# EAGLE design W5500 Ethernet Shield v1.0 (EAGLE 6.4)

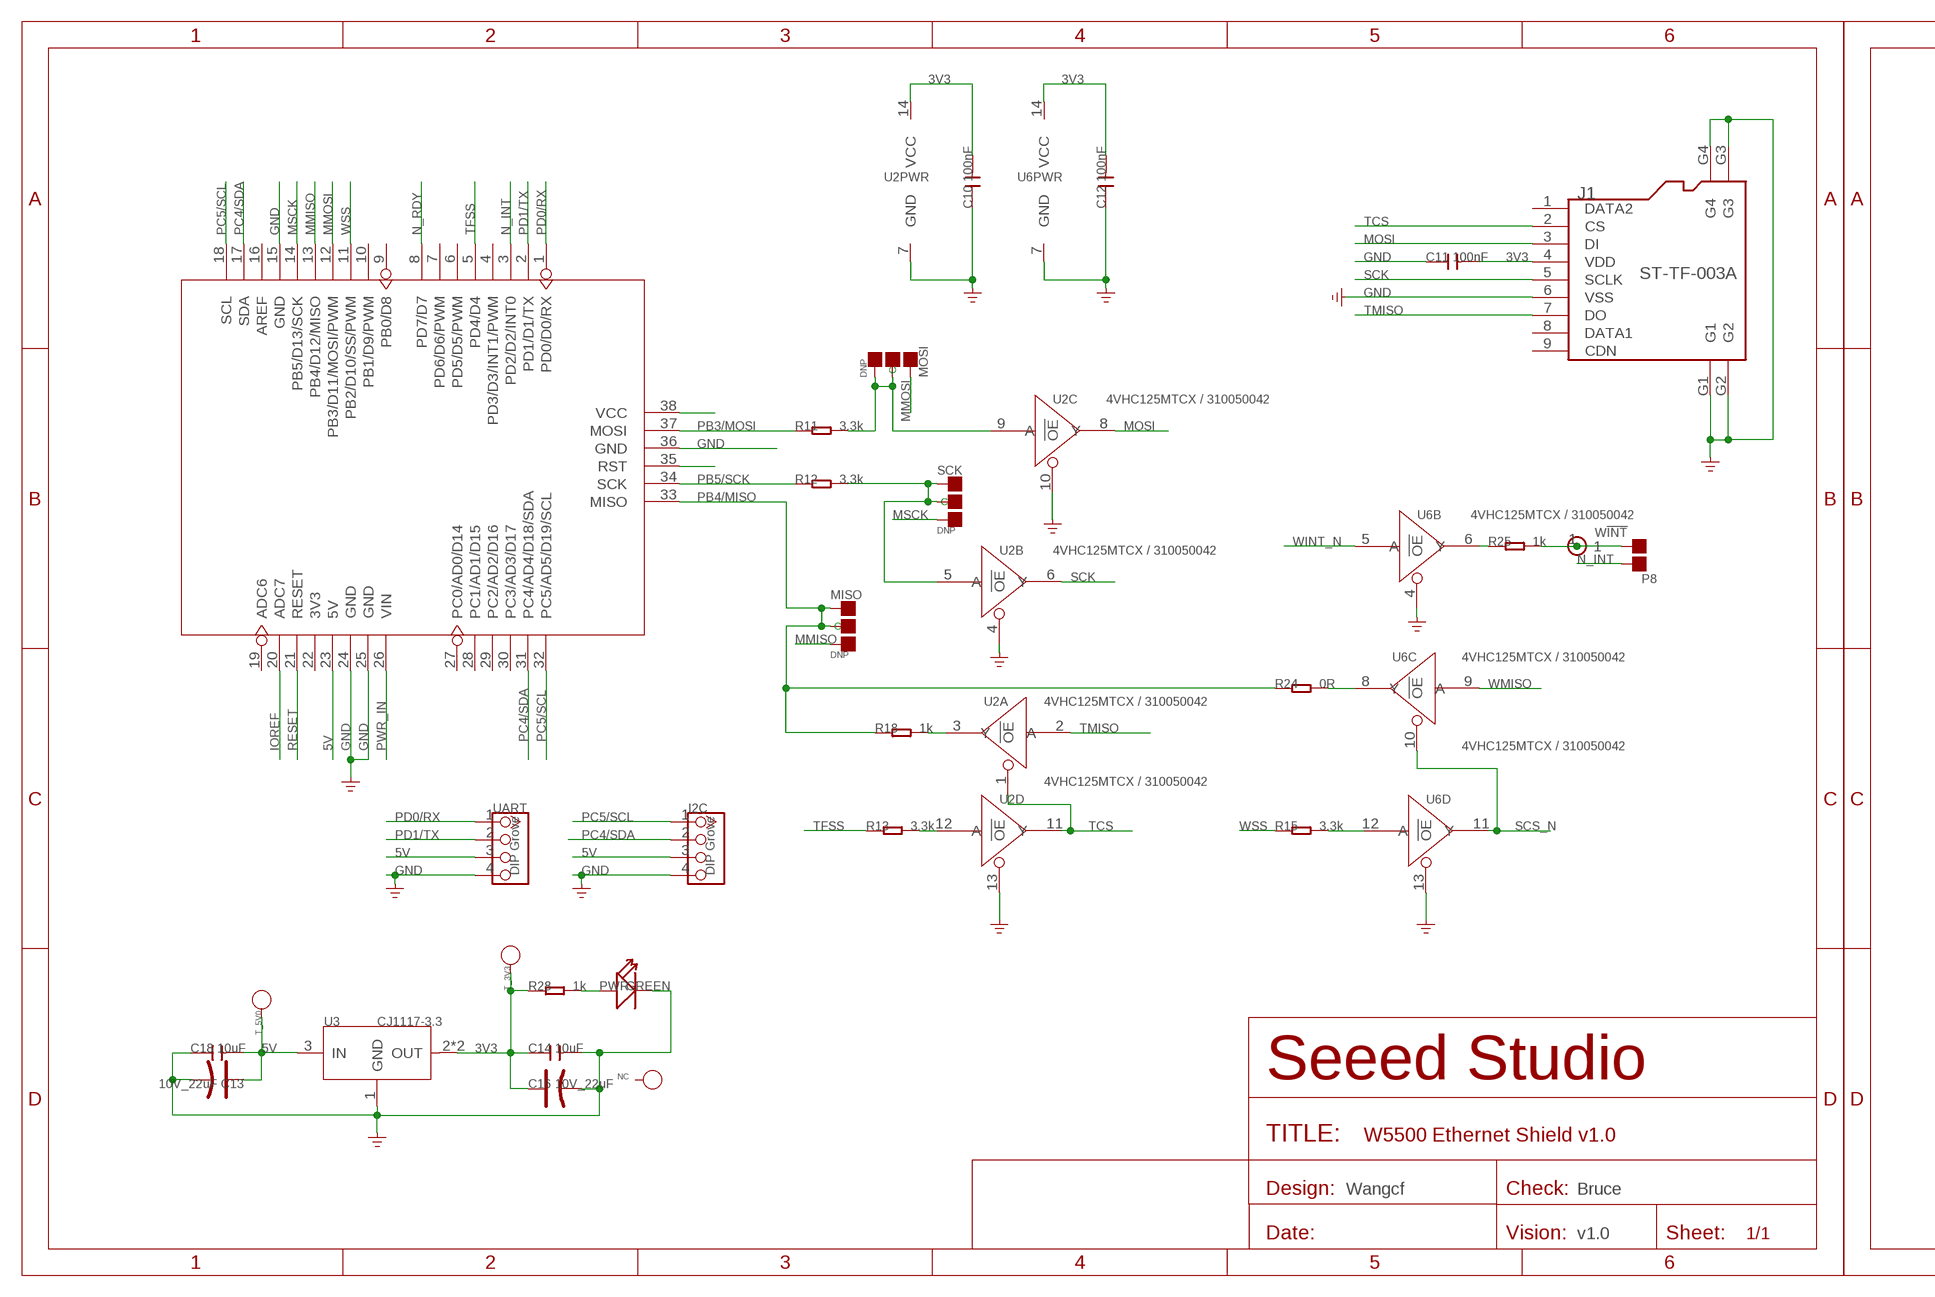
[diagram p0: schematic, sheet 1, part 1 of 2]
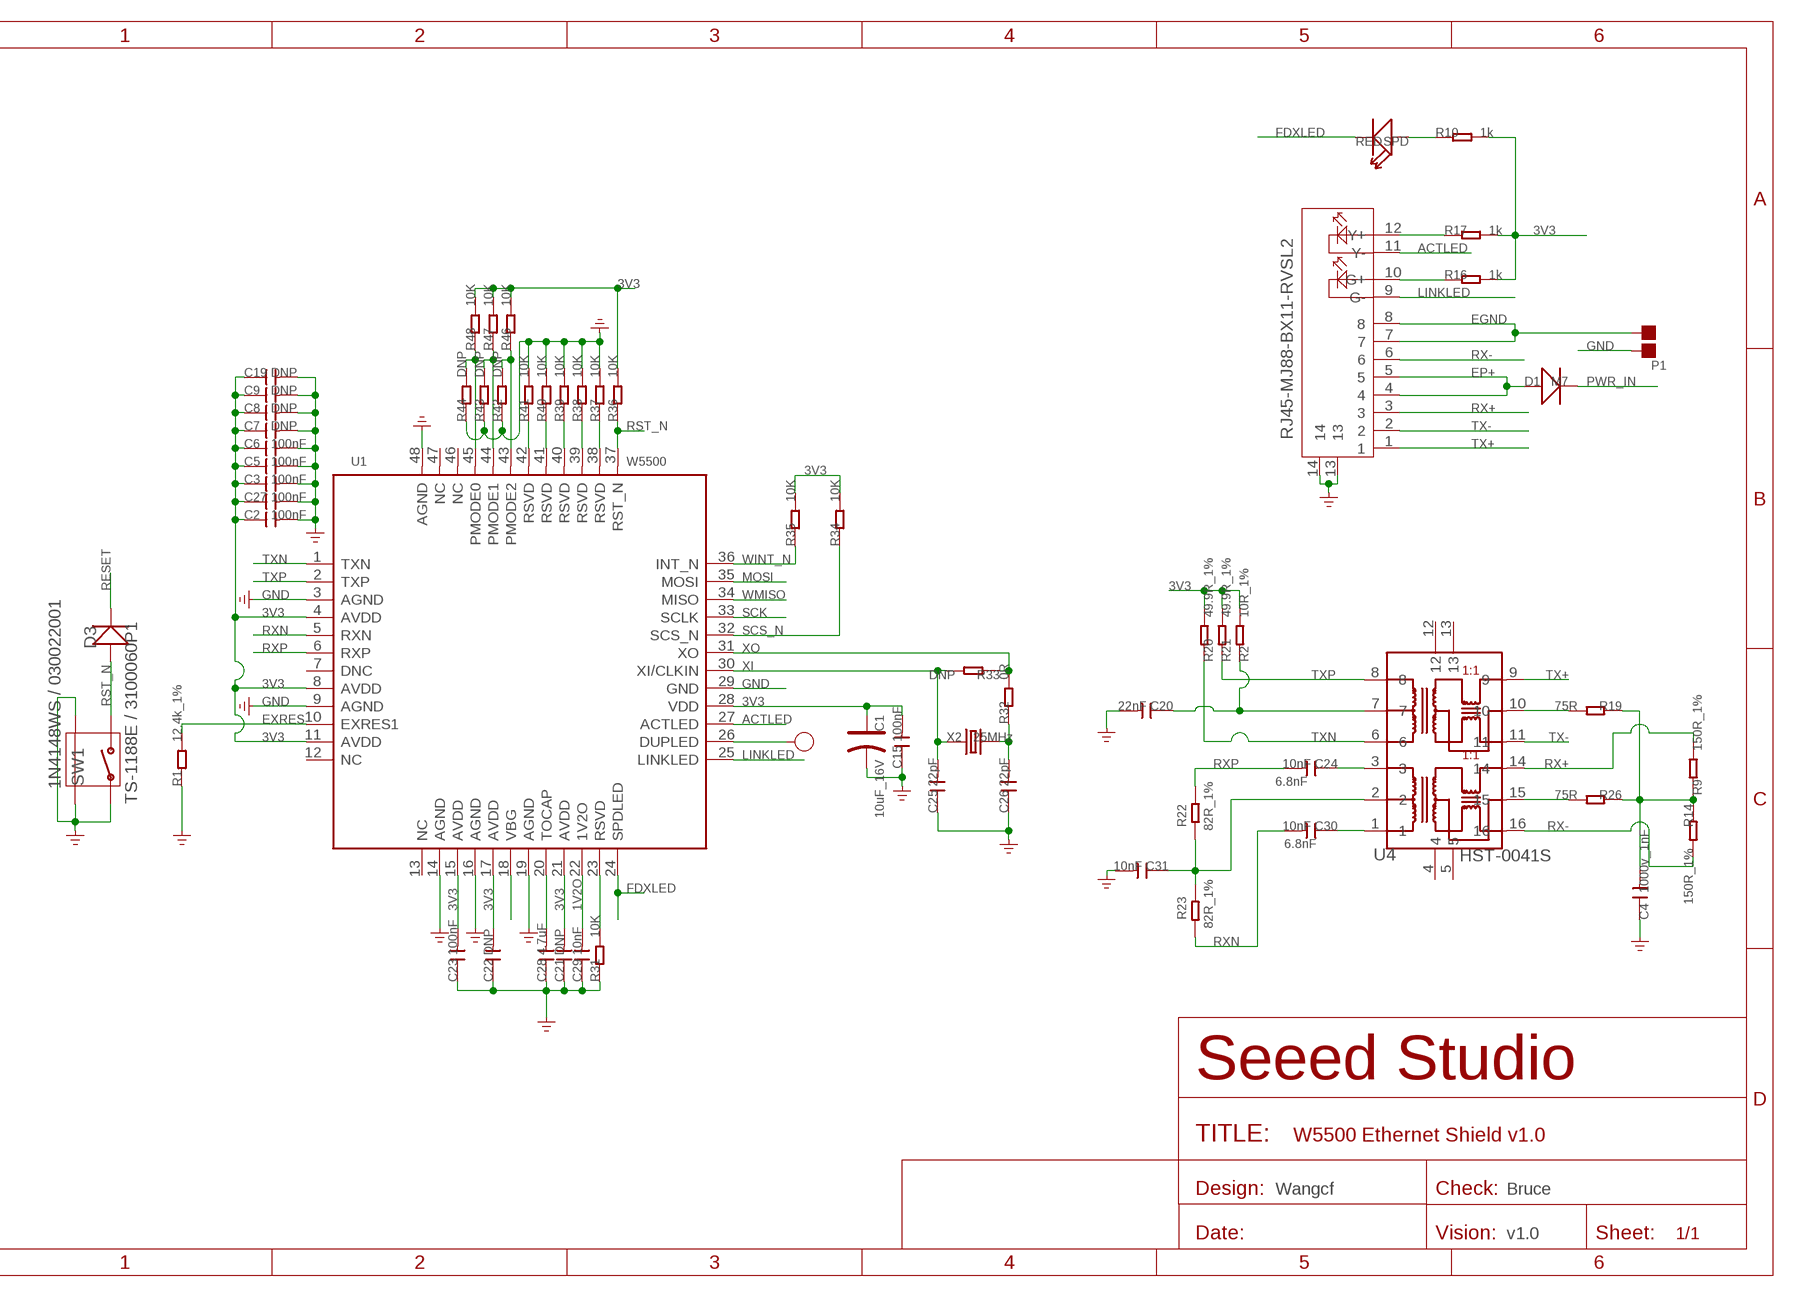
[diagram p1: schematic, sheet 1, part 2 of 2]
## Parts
C1  10uF_16V  CAP-POLAR-AVX-A  [AVX-A]
C2  100nF  C-0603  [C0603]
C3  100nF  C-0603  [C0603]
C4  1000v_1nF  C-1206  [C1206]
C5  100nF  C-0603  [C0603]
C6  100nF  C-0603  [C0603]
C7  DNP  C-0805  [C0805]
C8  DNP  C-0805  [C0805]
C9  DNP  C-0805  [C0805]
C10  100nF  C-0603  [C0603]
C11  100nF  C-0603  [C0603]
C12  100nF  C-0603  [C0603]
C13  10V_22uF  CAP-AVX-B  [AVX-B]
C14  10uF  C-0805  [C0805]
C15  100nF  C-0603  [C0603]
C16  10V_22uF  CAP-AVX-B  [AVX-B]
C18  10uF  C-0805  [C0805]
C19  DNP  C-0805  [C0805]
C20  22nF  C-0603  [C0603]
C21  DNP  C-0603  [C0603]
C22  DNP  C-0603  [C0603]
C23  100nF  C-0603  [C0603]
C24  10nF  C-0603  [C0603]
C25  22pF  C-0603  [C0603]
C26  22pF  C-0603  [C0603]
C27  100nF  C-0603  [C0603]
C28  4.7uF  C-0805  [C0805]
C29  10nF  C-0603  [C0603]
C30  10nF  C-0603  [C0603]
C31  10nF  C-0603  [C0603]
D1  M7  D'SMA'  [DO-214AC]
D3  1N4148WS / 030022001  D'0805'  [SOD323]
I2C  DIP Grove  TWIG-4P-2.0-2.0  [4P-2.0]
J1  ST-TF-003A  HOLDER-MICROSD-9P  [9P-SMD-W/-RING]
J8  RJ45-MJ88-BX11-RVSL2  [RJ45-MJ88-BX11-RVSL2]
MISO  DNP  PAD-JUMPER-3P-40*40  [3P-SMD-4.1X1.5]
MOSI  DNP  PAD-JUMPER-3P-40*40  [3P-SMD-4.1X1.5]
NC  PAD-TEST-POINT'4545'  [TP_4545]
P1  DNP  PAD-JUMPER-2P  [2P-SMD-1.78X1.27]
P8  DNP  PAD-JUMPER-2P  [2P-SMD-1.78X1.27]
PWR  GREEN  LED'0603'  [LED-0603]
R1  12.4k_1%  R-0603  [R0603]
R2  10R_1%  R-0603  [R0603]
R9  150R_1%  R-0603  [R0603]
R10  1k  R-0603  [R0603]
R11  3.3k  R-0603  [R0603]
R12  3.3k  R-0603  [R0603]
R13  3.3k  R-0603  [R0603]
R14  150R_1%  R-0603  [R0603]
R15  3.3k  R-0603  [R0603]
R16  1k  R-0603  [R0603]
R17  1k  R-0603  [R0603]
R18  1k  R-0603  [R0603]
R19  75R  R-0603  [R0603]
R20  49.9R_1%  R-0603  [R0603]
R21  49.9R_1%  R-0603  [R0603]
R22  82R_1%  R-0603  [R0603]
R23  82R_1%  R-0603  [R0603]
R24  0R  R-0603  [R0603]
R25  1k  R-0603  [R0603]
R26  75R  R-0603  [R0603]
R28  1k  R-0603  [R0603]
R31  10K  R-0603  [R0603]
R32  0R  R-0603  [R0603]
R33  DNP  R-0603  [R0603]
R34  10K  R-0603  [R0603]
R35  10K  R-0603  [R0603]
R36  10K  R-0603  [R0603]
R37  10K  R-0603  [R0603]
R38  10K  R-0603  [R0603]
R39  10K  R-0603  [R0603]
R40  10K  R-0603  [R0603]
R41  10K  R-0603  [R0603]
R42  DNP  R-0603  [R0603]
R43  DNP  R-0603  [R0603]
R44  DNP  R-0603  [R0603]
R46  10K  R-0603  [R0603]
R47  10K  R-0603  [R0603]
R48  10K  R-0603  [R0603]
SCK  DNP  PAD-JUMPER-3P-40*40  [3P-SMD-4.1X1.5]
SPD  RED  LED'0603'  [LED-0603]
SW1  TS-1188E / 3100060P1  BUTTON_4P_SMD  [4P-SMD-7X3.5X3.5]
T_3V3  PAD-TEST-POINT'4545'  [TP_4545]
T_5V0  PAD-TEST-POINT'4545'  [TP_4545]
TP6  PAD-TEST-POINT'4545'  [TP_4545]
U1  W5500  DRIVER-W5500  [LQFP-48]
U2  4VHC125MTCX / 310050042  74VHC125PW  [TSSOP14]
U3  CJ1117-3.3  LD1117S  [SOT-223]
U4  HST-0041S  [SOIC16-9.53]
U5  DNP  ARDUINO-38P'WITH-SILK'  [ARDUINO-DRILL-DIM]
U6  4VHC125MTCX / 310050042  74VHC125PW  [TSSOP14]
UART  DIP Grove  TWIG-4P-2.0-2.0  [4P-2.0]
W!INT  DNP  HEADER-1P-35  [1P-65/35MIL]
X2  25MHz  CRYSTAL'5032'  [2P-SMD-5X3.2]

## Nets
1V2O: C29.2 U1.22(1V2O)
3V3: C1.+ C2.1 C3.1 C5.1 C6.1 C7.1 C8.1 C9.1 C10.2 C11.2 C12.2 C14.1 C15.2 C16.+ C19.1 C21.2 C22.2 C23.2 C27.1 J1.4(VDD) R2.2 R10.2 R16.2 R17.2 R20.2 R21.2 R28.1 R34.2 R35.2 R36.2 R46.2 R47.2 R48.2 T_3V3.T U1.4(AVDD) U1.8(AVDD) U1.11(AVDD) U1.15(AVDD) U1.17(AVDD) U1.21(AVDD) U1.28(VDD) U2.14(PWR:VCC) U3.2(OUT) U3.TER(OUT) U6.14(PWR:VCC)
5V [usbvcc]: C13.+ C18.2 I2C.3 T_5V0.T U3.3(IN) U5.23(5V) UART.3
ACTLED: J8.11(Y-) U1.27(ACTLED)
EGND [power]: J8.7 J8.8 P1.1
EP+: D1.1(+) J8.4 J8.5
EXRES: R1.2 U1.10(EXRES1)
FDXLED: SPD.- U1.24(SPDLED)
GND: C1.- C2.2 C3.2 C4.1 C5.2 C6.2 C7.2 C8.2 C9.2 C10.1 C11.1 C12.1 C13.- C14.2 C15.1 C16.- C18.1 C19.2 C20.2 C21.1 C22.1 C23.1 C25.1 C26.1 C27.2 C28.1 C29.1 C31.2 I2C.4 J1.6(VSS) J1.G1 J1.G2 J1.G3 J1.G4 J8.13 J8.14 P1.2 PWR.- R1.1 R31.1 R37.2 R38.2 R39.2 R40.2 R41.2 R42.1 R43.1 R44.1 SW1.1 SW1.S1 SW1.S2 U1.3(AGND) U1.9(AGND) U1.14(AGND) U1.16(AGND) U1.19(AGND) U1.29(GND) U1.48(AGND) U2.4(B:!OE) U2.7(PWR:GND) U2.10(C:!OE) U2.13(D:!OE) U3.1(GND) U5.15(GND) U5.24(GND) U5.25(GND) U5.36(GND) U6.4(B:!OE) U6.7(PWR:GND) U6.13(D:!OE) UART.4
IOREF: U5.20(ADC7)
LINKLED: J8.9(G-) U1.25(LINKLED)
MMISO: MISO.11(R) U5.13(PB4/D12/MISO)
MMOSI: MOSI.00(L) U5.12(PB3/D11/MOSI/PWM)
MOSI: J1.3(DI) U1.35(MOSI) U2.8(C:Y)
MSCK: SCK.11(R) U5.14(PB5/D13/SCK)
N$1: U5.38(VCC)
N$2: U5.35(RST)
N$3: C20.1 R2.1 U4.7
N$4: MOSI.11(R) MOSI.MM(C) R11.2 U2.9(C:A)
N$6: R10.1 SPD.+
N$7: R12.2 SCK.00(L) SCK.MM(C) U2.5(B:A)
N$8: C24.1 U4.3
N$9: R13.2 U2.12(D:A)
N$10: R15.2 U6.12(D:A)
N$14: R18.2 U2.3(A:Y)
N$17: R24.2 U6.8(C:Y)
N$18: J8.12(Y+) R17.1
N$19: J8.10(G+) R16.1
N$20: R25.1 U6.6(B:Y)
N$21: P8.1 R25.2 W!INT.1
N$22: C30.1 U4.1
N$25: C31.1 R22.2 R23.2 U4.2
N$26: PWR.+ R28.2
N$27: R37.1 U1.38(RSVD)
N$28: C26.2 R32.1 X2.2
N$29: R26.2 U4.15
N$30: R38.1 U1.39(RSVD)
N$31: R39.1 U1.40(RSVD)
N$32: R40.1 U1.41(RSVD)
N$33: R41.1 U1.42(RSVD)
N$35: R42.2 R46.1 U1.43(PMODE2)
N$36: R43.2 R47.1 U1.44(PMODE1)
N$37: R44.2 R48.1 U1.45(PMODE0)
N$42: R19.2 U4.10
N$43: C4.2 R9.1 R14.1 R19.1 R26.1
N$45: U1.18(VBG)
N$50: R31.2 U1.23(RSVD)
N$53: TP6.T U1.26(DUPLED)
N_INT: P8.2 U5.3(PD2/D2/INT0)
N_RDY: U5.8(PD7/D7)
PB3/MOSI: R11.1 U5.37(MOSI)
PB4/MISO: MISO.00(L) MISO.MM(C) R18.1 R24.1 U5.33(MISO)
PB5/SCK: R12.1 U5.34(SCK)
PC4/SDA: I2C.2 U5.17(SDA) U5.31(PC4/AD4/D18/SDA)
PC5/SCL: I2C.1 U5.18(SCL) U5.32(PC5/AD5/D19/SCL)
PD0/RX: U5.1(PD0/D0/RX) UART.1
PD1/TX: U5.2(PD1/D1/TX) UART.2
PWR_IN: D1.2(-) U5.26(VIN)
RESET: D3.- U5.21(RESET)
RST_N: D3.+ R36.1 SW1.2 U1.37(RST_N)
RX+: J8.3 R9.2 U4.14
RX-: J8.6 R14.2 U4.16
RXN: C30.2 R23.1 U1.5(RXN)
RXP: C24.2 R22.1 U1.6(RXP)
SCK: J1.5(SCLK) U1.33(SCLK) U2.6(B:Y)
SCS_N: R34.1 U1.32(SCS_N) U6.10(C:!OE) U6.11(D:Y)
TCS: J1.2(CS) U2.1(A:!OE) U2.11(D:Y)
TFSS: R13.1 U5.5(PD4/D4)
TMISO: J1.7(DO) U2.2(A:A)
TOCAP: C28.2 U1.20(TOCAP)
TX+: J8.1 U4.9
TX-: J8.2 U4.11
TXN: R20.1 U1.1(TXN) U4.6
TXP: R21.1 U1.2(TXP) U4.8
WINT_N: R35.1 U1.36(INT_N) U6.5(B:A)
WMISO: U1.34(MISO) U6.9(C:A)
WSS: R15.1 U5.11(PB2/D10/SS/PWM)
XI: C25.2 R33.2 U1.30(XI/CLKIN) X2.1
XO: R32.2 R33.1 U1.31(XO)
Unconnected: J1.1(DATA2) J1.8(DATA1) J1.9(CDN) NC.T U1.7(DNC) U1.12(NC) U1.13(NC) U1.46(NC) U1.47(NC) U4.4 U4.5 U4.12 U4.13 U5.4(PD3/D3/INT1/PWM) U5.6(PD5/D5/PWM) U5.7(PD6/D6/PWM) U5.9(PB0/D8) U5.10(PB1/D9/PWM) U5.16(AREF) U5.19(ADC6) U5.22(3V3) U5.27(PC0/AD0/D14) U5.28(PC1/AD1/D15) U5.29(PC2/AD2/D16) U5.30(PC3/AD3/D17) U6.1(A:!OE) U6.2(A:A) U6.3(A:Y)

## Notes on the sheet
- 6.8nF
- 6.8nF
- Wangcf | Bruce | Wangcf | Bruce
- v1.0 | v1.0

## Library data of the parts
C1 = Discrete-new:CAP-POLAR: Electrolytic Capacitors,Tantalum Capacitors and Super Capacitors
C2-C12 C14 C15 C18-C31 = Discrete:C*: Ceramic Capacitors
C13 C16 = Discrete:CAP*: Electrolytic Capacitors,Tantalum Capacitors and Super Capacitors
D1 D3 = Discrete:D*
I2C UART = Connector:TWIG-4P-2.0
J1 = Connector :HOLDER-MICROSD-9P
J8 = Connector:RJ45-MJ88-BX11-RVSL2: Modular Jack 8P8C,R/A,With LED
MISO MOSI SCK = Discrete:PAD-JUMPER-3P
NC T_3V3 T_5V0 TP6 = Discrete:PAD-TEST-POINT; PARTNO: DNP
P1 P8 = Discrete:PAD-JUMPER-2P; PARTNO: DNP
PWR SPD = Discrete:LED*
R1 R2 R9-R26 R28 R31-R44 R46-R48 = Discrete:R*
SW1 = For_Test_Albert_v6:BUTTON_4P_SMD: TS-1188E http://www.best-dz.com/?thread-374-2.html
U1 = template:DRIVER-W5500
U2 U6 = IC:74V*125: Quad Buffer/Line Driver;3-state
U3 = IC:LD1117: Low Drop Fixed And Adjustable Positive Voltage Regulators http://www.datasheetcatalog.org/datasheet/SGSThomsonMicroelectronics/mXuqtqv.pdf
U4 = template:HST-0041S: 10/100BASE-T Single Port Surface Mount Magnetics With Various Turns Ratios
U5 = moudle-new:ARDUINO-38P: 206000005
W!INT = Connector:HEADER-1P
X2 = Discrete:CRYSTAL*: CRYSTAL

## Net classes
0 default: width 0.203 mm, drill 0.305 mm, clearance 0.203 mm
3 usbvcc: width 0.203 mm, drill 0.305 mm, clearance 0.203 mm

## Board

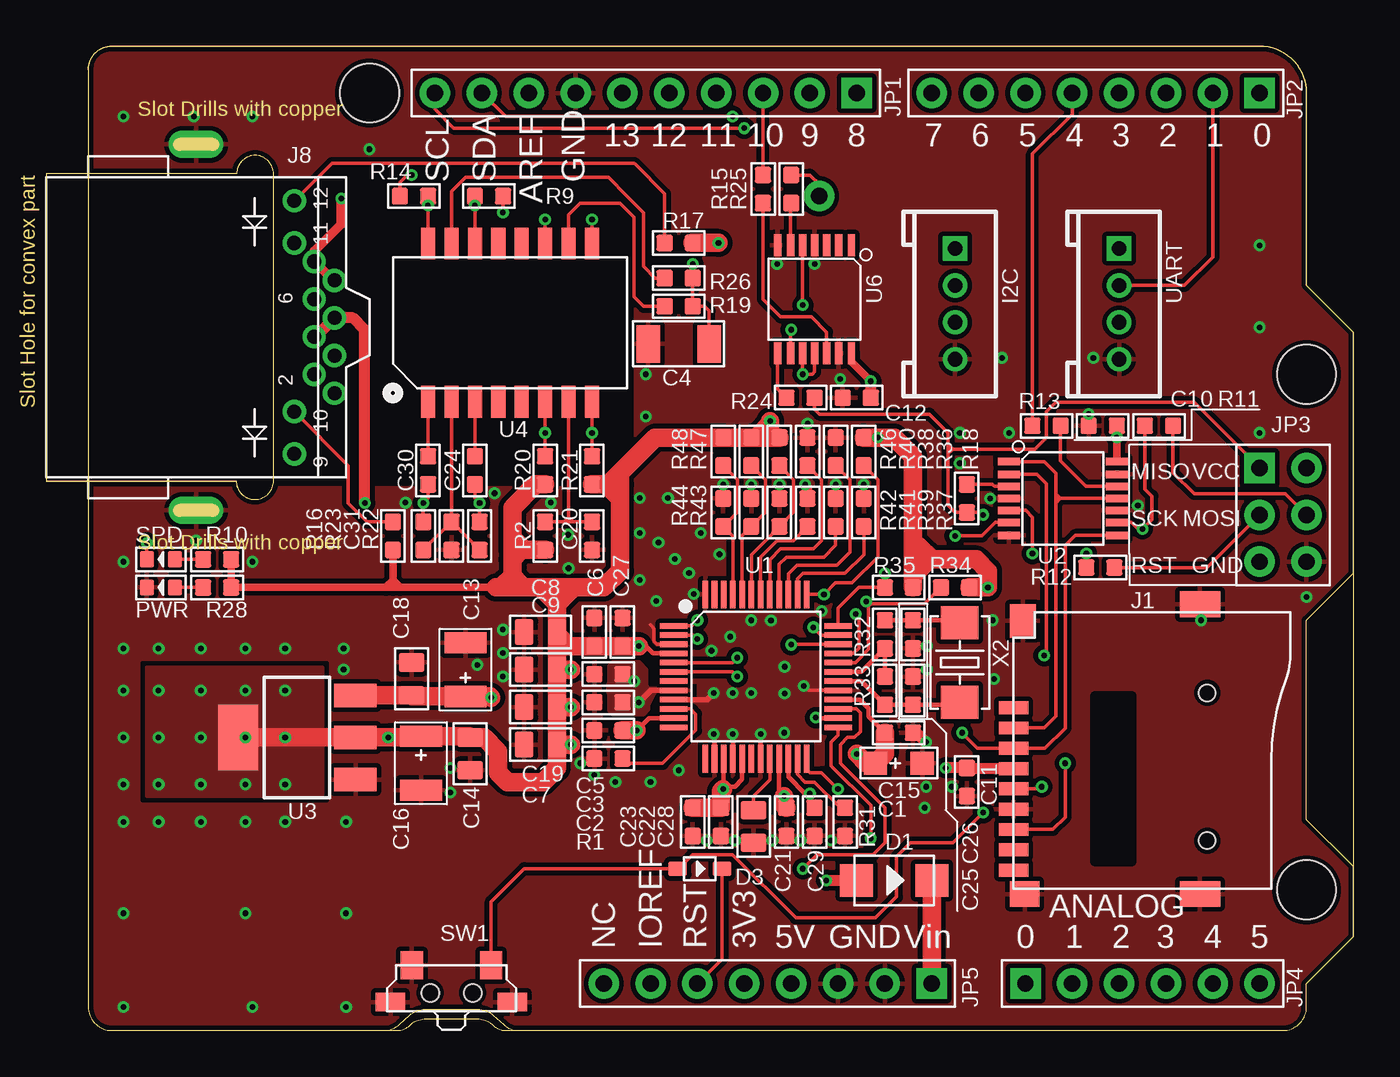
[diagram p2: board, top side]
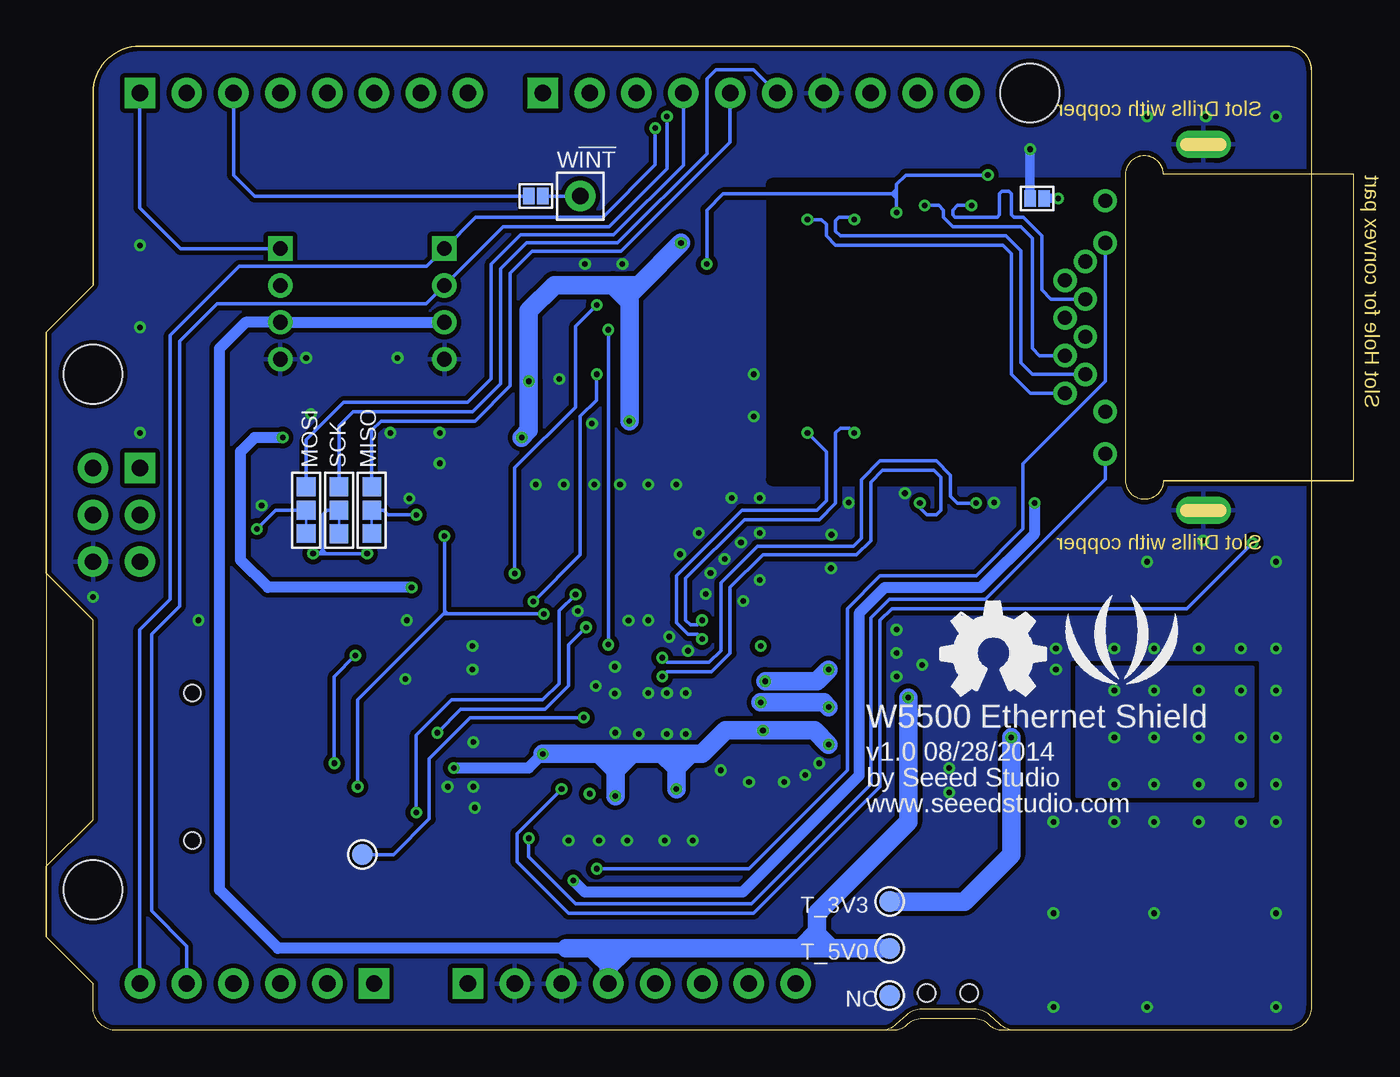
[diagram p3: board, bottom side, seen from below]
Size 70.87 x 53.34 mm. Coordinates in mm from the lower left corner, seen from the top.
Outline: 2.29,52.07 2.29,1.27 arc90 3.56,0 18.31,0 arc42 19.16,0.33 19.71,0.82 arc-42 20.55,1.14 23.39,1.14 arc-42 24.24,0.82 24.79,0.33 arc42 25.64,0 67.06,0 arc90 68.33,1.27 68.33,2.54 70.87,5.08 70.87,8.89 68.33,11.43 68.33,22.23 70.87,24.77 70.87,37.85 68.33,40.39 68.33,50.8 arc90 65.79,53.34 3.56,53.34 arc90 2.29,52.07
Copper layers (1*16): Top 0.035mm / dielectric 1.5mm / Bottom 0.035mm
Design rules "default *": minimum track width 6mil, minimum drill 12mil, track to track 6mil, track to pad 6mil, pad to pad 6mil, via to via 6mil, smd to smd 0mil, copper to edge 10mil, drill to drill 10mil, minimum pad ring 10mil, minimum via ring 6mil, stop-mask expansion 2mil, vias tented up to drill 25mil, thermal gap 10mil
tRestrict: area 12.4,29.8 to 31.5,45.8
bRestrict: 4 lines

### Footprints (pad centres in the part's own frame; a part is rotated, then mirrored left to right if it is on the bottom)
AVX-A = smd 1.27 x 1.27: + -1.27,0; - 1.27,0
C0603 = smd 0.889 x 0.889: 1 -0.762,0; 2 0.762,0
C1206 = smd 1.27 x 2.032: 1 -1.651,0; 2 1.651,0
C0805 = smd 1.016 x 1.397: 1 -0.889,0; 2 0.889,0
AVX-B = smd 1.143 x 2.286: + -1.46,0; - 1.46,0
DO-214AC = smd 1.8 x 1.77: 1 -2.042,0; 2 2.042,0
SOD323 = smd 1 x 0.8: + -1.2,0; - 1.2,0
4P-2.0 = drill 0.8 pad 1.27 square: 1 -3,0 | drill 0.8 pad 1.27: 2 -1,0; 3 1,0; 4 3,0
9P-SMD-W/-RING = smd 1.6 x 0.7: 1 0,2.25; 2 0,1.15; 3 0,0.05; 4 0,-1.05; 5 0,-2.15; 6 0,-3.25; 7 0,-4.35; 8 0,-5.45; 9 0,-6.55 | smd 1.6 x 1.4: G1 0.6,-7.85 | smd 2.2 x 1.4: G2 10.1,-7.85; G3 10.1,7.85 | smd 1.4 x 1.8: G4 0.5,6.95 | hole 0.9: 10.5,-4.95; 10.5,3.05
RJ45-MJ88-BX11-RVSL2 = drill 0.762 pad 1.27: 1 3.57,7.5; 2 2.55,6.4; 3 1.53,7.5; 4 0.51,6.4; 5 -0.51,7.5; 6 -1.53,6.4; 7 -2.55,7.5; 8 -3.57,6.4; 9 6.86,5.32; 10 4.57,5.32; 11 -4.57,5.32; 12 -6.86,5.32 | drill 0.6 pad 1.5 long: 13 -9.92,0; 14 9.92,0
3P-SMD-4.1X1.5 = smd 1.016 x 1.016: 00 -1.27,0; 11 1.27,0; MM 0,0
TP_4545 = smd 1.143 x 1.143: T 0,0
2P-SMD-1.78X1.27 = smd 0.889 x 0.61: 1 0,0.381; 2 0,-0.381
LED-0603 = smd 0.762 x 0.889: + -0.762,0; - 0.762,0
R0603 = smd 0.889 x 0.889: 1 -0.762,0; 2 0.762,0
4P-SMD-7X3.5X3.5 = smd 1.2 x 1.5: 1 -2.15,1.5; 2 2.15,1.5 | smd 1.6 x 1: S1 -3.3,-0.5; S2 3.3,-0.5 | hole 0.95: -1.15,0; 1.15,0
LQFP-48 = smd 1.5 x 0.3: 1 -4.45,2.75; 2 -4.45,2.25; 3 -4.45,1.75; 4 -4.45,1.25; 5 -4.45,0.75; 6 -4.45,0.25; 7 -4.45,-0.25; 8 -4.45,-0.75; 9 -4.45,-1.25; 10 -4.45,-1.75; 11 -4.45,-2.25; 12 -4.45,-2.75; 25 4.45,-2.75; 26 4.45,-2.25; 27 4.45,-1.75; 28 4.45,-1.25; 29 4.45,-0.75; 30 4.45,-0.25; 31 4.45,0.25; 32 4.45,0.75; 33 4.45,1.25; 34 4.45,1.75; 35 4.45,2.25; 36 4.45,2.75 | smd 0.3 x 1.5: 13 -2.75,-4.45; 14 -2.25,-4.45; 15 -1.75,-4.45; 16 -1.25,-4.45; 17 -0.75,-4.45; 18 -0.25,-4.45; 19 0.25,-4.45; 20 0.75,-4.45; 21 1.25,-4.45; 22 1.75,-4.45; 23 2.25,-4.45; 24 2.75,-4.45; 37 2.75,4.45; 38 2.25,4.45; 39 1.75,4.45; 40 1.25,4.45; 41 0.75,4.45; 42 0.25,4.45; 43 -0.25,4.45; 44 -0.75,4.45; 45 -1.25,4.45; 46 -1.75,4.45; 47 -2.25,4.45; 48 -2.75,4.45
TSSOP14 = smd 0.4 x 1.2: 1 -2,-2.925; 2 -1.3,-2.925; 3 -0.65,-2.925; 4 0,-2.925; 5 0.65,-2.925; 6 1.3,-2.925; 7 2,-2.925; 8 2,2.925; 9 1.3,2.925; 10 0.65,2.925; 11 0,2.925; 12 -0.65,2.925; 13 -1.3,2.925; 14 -2,2.925
SOT-223 = smd 1.27 x 2.286: 1 -2.286,-3.175; 2 0,-3.175; 3 2.286,-3.175 | smd 3.556 x 2.159: TER 0,3.175
SOIC16-9.53 = smd 0.762 x 1.714: 1 -4.445,-4.286; 2 -3.175,-4.286; 3 -1.905,-4.286; 4 -0.635,-4.286; 5 0.635,-4.286; 6 1.905,-4.286; 7 3.175,-4.286; 8 4.445,-4.286; 9 4.445,4.286; 10 3.175,4.286; 11 1.905,4.286; 12 0.635,4.286; 13 -0.635,4.286; 14 -1.905,4.286; 15 -3.175,4.286; 16 -4.445,4.286
ARDUINO-DRILL-DIM = drill 0.889 pad 1.651 square: 1 63.5,50.8; 9 41.656,50.8; 26 45.72,2.54; 27 50.8,2.54; 33 63.5,30.48 | drill 0.889 pad 1.651: 2 60.96,50.8; 3 58.42,50.8; 4 55.88,50.8; 5 53.34,50.8; 6 50.8,50.8; 7 48.26,50.8; 8 45.72,50.8; 10 39.116,50.8; 11 36.576,50.8; 12 34.036,50.8; 13 31.496,50.8; 14 28.956,50.8; 15 26.416,50.8; 16 23.876,50.8; 17 21.336,50.8; 18 18.796,50.8; 19 27.94,2.54; 20 30.48,2.54; 21 33.02,2.54; 22 35.56,2.54; 23 38.1,2.54; 24 40.64,2.54; 25 43.18,2.54; 28 53.34,2.54; 29 55.88,2.54; 30 58.42,2.54; 31 60.96,2.54; 32 63.5,2.54; 34 63.5,27.94; 35 63.5,25.4; 36 66.04,25.4; 37 66.04,27.94; 38 66.04,30.48 | hole 3.2: 15.24,50.8; 66.04,35.56; 66.04,7.62
1P-65/35MIL = drill 0.889 pad 1.651: 1 0,0
2P-SMD-5X3.2 = smd 1.778 x 2.032: 1 -2.159,0; 2 2.159,0

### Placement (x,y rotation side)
C1  46.23,14.48 0 top
C2  30.48,16.26 180 top
C3  30.48,17.78 180 top
C4  34.29,37.21 0 top
C5  30.48,19.3 180 top
C6  29.72,21.59 90 top
C7  26.8,15.49 180 top
C8  26.8,21.59 180 top
C9  26.8,19.56 180 top
C10  57.28,32.77 0 top
C11  49.91,13.46 90 top
C12  43.94,34.29 0 top
C13  22.73,19.56 90 top
C14  22.99,14.99 270 top
C15  46.23,16.13 180 top
C16  20.32,14.48 270 top
C18  19.81,19.05 270 top
C19  26.8,17.53 180 top
C20  29.59,26.8 270 top
C21  40.13,11.3 90 top
C22  36.58,11.3 90 top
C23  35.05,11.3 90 top
C24  23.24,30.35 270 top
C25  46.99,18.41 270 top
C26  46.99,21.46 90 top
C27  31.24,21.59 90 top
C28  38.36,11.05 90 top
C29  41.66,11.3 90 top
C30  20.7,30.35 270 top
C31  21.97,26.8 270 top
D1  45.98,8.13 0 top
D3  35.44,8.76 0 top
I2C  49.28,39.37 270 top
J1  52.45,15.24 0 top
J8  8.13,38.1 270 top
MISO  53.22,28.19 90 bottom
MOSI  56.77,28.19 270 bottom
NC  25.15,1.91 0 bottom
P1  17.15,45.09 270 bottom
P8  44.33,45.21 270 bottom
PWR  6.23,24 180 top
R1  30.48,14.73 0 top
R2  27.05,26.8 270 top
R9  24,45.21 180 top
R10  9.27,25.53 0 top
R11  60.33,32.77 180 top
R12  57.15,25.08 180 top
R13  54.23,32.77 0 top
R14  19.94,45.21 0 top
R15  38.86,45.59 270 top
R16  18.8,26.8 270 top
R17  34.29,42.67 0 top
R18  49.91,28.83 90 top
R19  34.29,39.24 180 top
R20  27.05,30.35 270 top
R21  29.59,30.35 270 top
R22  23.5,26.8 270 top
R23  20.45,26.8 270 top
R24  40.9,34.29 180 top
R25  40.39,45.59 90 top
R26  34.29,40.77 180 top
R28  9.27,24 180 top
R31  43.31,11.3 90 top
R32  45.47,21.46 270 top
R33  45.47,18.41 270 top
R34  49.28,24 0 top
R35  46.23,24 0 top
R36  44.33,31.37 90 top
R37  44.33,28.07 90 top
R38  42.8,31.37 90 top
R39  42.8,28.07 90 top
R40  41.28,31.37 90 top
R41  41.28,28.07 90 top
R42  39.75,28.07 270 top
R43  38.23,28.07 270 top
R44  36.71,28.07 270 top
R46  39.75,31.37 90 top
R47  38.23,31.37 90 top
R48  36.71,31.37 90 top
SCK  54.99,28.19 90 bottom
SPD  6.23,25.53 180 top
SW1  21.97,2.03 0 top
T_3V3  25.15,6.99 0 bottom
T_5V0  25.15,4.45 0 bottom
TP6  53.72,9.53 180 bottom
U1  38.48,19.18 0 top
U2  55.12,28.83 270 top
U3  13.59,15.88 90 top
U4  25.15,38.35 0 top
U5  2.29,0 0 top
U6  41.66,39.62 180 top
U$23  [LOGO_SILK]  12.58,20.45 0 bottom
U$25  [OSHW_FILLX200_NOTEXT]  22.35,18.16 0 bottom
UART  58.17,39.37 270 top
W!INT  41.91,45.21 180 bottom
X2  49.53,19.94 90 top

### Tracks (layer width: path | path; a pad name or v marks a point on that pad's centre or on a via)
1V2O  (via drill 0.3 pad 0.64)
  Top 0.254: U1.22 40.23,13.74 41.15,12.83 v41.4,12.83 41.4,12.32 C29.2
3V3  (via drill 0.3 pad 0.64)
  Top 0.254: U1.11 32.68,16.93 v32.01,16.26 | U1.15 36.73,13.21 | 36.73,13.21 36.73,13.11 v36.71,13.08 | U1.17 37.73,13.6 37.34,13.21 36.73,13.21 | U1.21 39.73,12.97 v40.01,12.7 | U1.4 34.01,20.45 32.9,20.45 32.51,20.83 v32.13,20.83 | U1.28 44.11,17.93 44.58,17.46 44.58,17.02 C15.2
  Top 0.305: U1.8 32.78,18.43 v32.13,17.78
  Top 0.406: U6.14 43.66,36.23 v44.71,35.18 | R10.2 R28.1 18.42,24 | 18.8,24 18.8,24.38 | 18.8,24.38 R16.2 | 24.39,24 19.18,24 | 19.18,24 18.8,24 | 18.8,24 18.42,24 | 18.8,24.38 18.42,24 | 18.8,24.38 19.18,24 | U2.14 v58.05,32.13 v58.04,32.13
  Top 0.61: C12.2 v44.71,35.18 | v48.77,14.22 C11.2 49.95,14.19 J1.4 | C10.2 v58.04,32.13
  Top 1.016: U3.TER U3.2 v18.54,15.88 20.26,15.88 C16.+ 22.93,15.94 C14.1 23.75,15.88 24.51,15.11 24.51,13.97 25.02,13.46 26.93,13.46 27.69,14.22 C7.1 | C9.1 v28.45,19.56 | C19.1 v28.45,17.53 | C7.1 v28.45,15.49 | C2.1 v32.01,16.26 | C8.1 27.69,21.46 28.32,20.83 C6.1 C27.1 v32.13,20.83 | C7.1 C19.1 | C9.1 C8.1 | C19.1 C9.1 | C23.2 C22.2 36.58,12.95 v36.71,13.08 | 46.99,24.89 R35.2 46.99,25.53 | 46.99,25.53 46.99,31.11 45.98,32.13 v45.09,32.13 R36.2 | 48.01,25.53 50.42,25.53 51.06,24.89 v51.06,24 R34.2 | 48.01,25.53 47.88,25.53 | 47.88,25.53 46.99,25.53 | 48.01,25.53 47.25,26.29 | 47.88,25.53 47.12,24.77 | 39.25,32.13 R47.2 R48.2 33.02,32.13 31.12,30.23 | 39.25,32.13 R46.2 | v39.25,33.02 39.25,32.89 | 39.25,32.89 39.25,32.13 | 39.25,32.89 38.61,32.26 | v36.45,42.67 R17.2 | 24.39,24 24.64,24 | 24.64,24 25.27,24 | 25.27,24 26.8,24 | 26.8,24 27.69,24 | 27.69,24 30.23,24 31.12,24.89 31.12,28.83 | 31.12,28.83 31.12,29.59 | 31.12,29.59 31.12,30.23 | R21.2 30.48,29.59 | 30.48,29.59 31.12,29.59 | 30.48,29.59 31.12,30.23 | 30.48,29.59 30.48,29.46 31.12,28.83 | R20.2 26.55,29.59 25.27,28.32 25.27,26.67 | C8.1 27.69,23.11 | 27.69,23.11 27.69,23.24 | 27.69,23.24 27.69,24 | 27.69,23.24 27.82,23.24 28.45,23.88 | 27.69,23.11 26.8,24 | R2.2 25.91,26.04 | 25.91,26.04 25.78,26.04 | 25.78,26.04 25.27,26.04 | 25.78,26.04 25.27,25.53 | 25.27,26.04 25.27,26.67 | 25.27,26.04 25.27,24.64 | 25.27,24.64 25.27,24 | 25.91,26.04 25.27,26.67 | 25.27,24.64 25.78,24.13 | 25.27,24.64 24.64,24 | C15.2 45.47,14.99 C1.+ 44.45,14.48 v43.94,14.99 | v40.01,12.7 40.01,12.19 C21.2
  Bottom 0.61: v51.06,24 58.84,24 60.33,25.49 60.33,31.37 59.57,32.13 v58.04,32.13 | v48.77,14.22 44.71,14.22 v43.94,14.99
  Bottom 1.016: v28.45,17.53 28.7,17.78 v32.13,17.78 | v28.45,19.56 29.09,18.92 v31.88,18.92 | v28.45,15.49 29.21,16.26 v32.01,16.26 34.04,16.26 35.31,14.99 35.94,14.99 | v45.09,32.13 44.71,32.51 v44.71,35.18 44.71,38.99 43.31,40.39 40.13,40.39 | T_3V3.T 21.08,6.99 18.54,9.53 v18.54,15.88 | v43.94,14.99 40.01,14.99 | 40.01,14.99 37.47,14.99 | 37.47,14.99 36.71,14.99 | 36.71,14.99 35.94,14.99 | v36.71,13.08 36.71,14.22 | 36.71,14.22 36.71,14.99 | v40.01,12.7 40.01,14.1 | 40.01,14.1 40.01,14.99 | 36.71,14.22 35.94,14.99 | 36.71,14.22 37.47,14.99 | 40.01,14.1 40.77,14.86 | 40.01,14.1 39.25,14.86 | 40.13,40.39 39.25,40.39 | 39.25,40.39 38.74,40.39 | 38.74,40.39 v36.45,42.67 | v39.25,33.02 39.25,39.62 | 39.25,39.88 39.25,40.39 | 39.25,39.62 39.37,39.62 40.13,40.39 | 39.25,39.62 39.25,39.88 | 39.25,39.88 38.74,40.39
  other vias: 6.1,13.34 6.1,15.88 6.1,18.41 8.38,18.41 8.38,15.88 8.38,13.34 10.8,13.34 10.8,15.88 10.8,18.41 12.96,13.34 12.96,15.88 12.96,18.41
  pour Top (isolate 0.254, no thermals): 34.85,18.52 32.67,18.52 32.51,18.67 32.51,19.56 32.13,19.94 30.74,19.94 30.48,19.68 30.48,17.4 30.74,17.14 32.39,17.14 32.64,17.4 32.64,17.65 32.95,18.34 34.98,18.34 34.93,18.41 34.93,18.44
  pour Top (isolate 0.254, no thermals): 14.99,12.7 14.99,19.68 5.46,19.68 5.46,12.7
  pour Bottom (isolate 0.254, no thermals): 14.99,12.7 14.99,19.68 5.46,19.68 5.46,12.7
5V  (via drill 0.3 pad 0.64)
  Top 1.016: v24.13,18.03 24.07,18.1 C13.+ 19.88,18.1 C18.2 U3.3
  Bottom 0.61: I2C.3 UART.3 60.06,38.37 61.47,36.96 61.47,7.62 58.3,4.45 42.67,4.45
  Bottom 1.016: v24.13,18.03 24.13,11.3 29.09,6.35 29.09,5.33 | T_5V0.T 28.32,4.45 | 28.32,4.45 29.21,4.45 | 29.21,4.45 40.39,4.45 | 40.39,4.45 42.67,4.45 | 29.09,5.21 29.09,4.57 29.21,4.45 | 29.09,5.33 29.85,4.57 | 29.09,5.33 29.09,5.21 | 29.09,5.21 28.32,4.45 | U5.23 40.39,3.56 | 40.39,3.56 40.39,4.45 | 40.39,3.56 41.02,4.19 | 40.39,3.56 40.26,3.56 39.63,4.19
ACTLED  (via drill 0.3 pad 0.64)
  Top 0.203: v41.02,8.76 41.79,9.53 44.83,9.53 45.47,10.16 45.47,12.06 43.06,14.48 43.06,15.49 43.44,15.88 43.82,15.88 44.13,16.19 44.13,17.21 43.92,17.43 U1.27
  Bottom 0.203: v41.02,8.76 32.77,8.76 27.43,14.1 27.43,22.86 25.66,24.64 20.45,24.64 17.91,27.18 17.91,30.72 13.45,35.18 J8.11
EGND  (via drill 0.3 pad 0.64)
  Top 0.508: J8.7 15.55,40.65 J8.8 14.53,42.21 16,43.69 v16,45.09
  Bottom 0.508: P1.1 v16,45.09
EP+  (via drill 0.3 pad 0.64)
  Top 0.61: J8.4 14.61,37.59 J8.5 16.64,38.61 17.27,37.97 v17.27,28.57 | v42.29,8.13 D1.1
  Bottom 0.61: v42.29,8.13 41.67,7.5 33.11,7.5 26.8,13.81 26.8,22.61 25.4,24 20.2,24 17.27,26.92 v17.27,28.57
EXRES
  Top 0.203: R1.2 31.5,14.48 33.43,14.48 35.21,16.26 35.21,17.14 34.92,17.43 U1.10
FDXLED  (via drill 0.3 pad 0.64)
  Top 0.203: SPD.- v5.46,26.42 | v42.93,13.08 42.04,13.97 41.4,13.97 41.23,14.14 U1.24
  Bottom 0.203: v5.46,26.42 9.02,22.86 25.02,22.86 25.66,22.23 25.66,13.21 32.51,6.35 42.55,6.35 45.34,9.14 45.34,10.67 v42.93,13.08
GND  (via drill 0.3 pad 0.64)
  Top 0.203: R44.1 v36.71,29.59 | U1.3 33.11,20.93 32.96,21.08 32.96,21.78 32.77,21.97 | U1.29 41.32,18.43 v41.07,18.67
  Top 0.254: U1.19 v38.73,16.06 v38.74,16.07 | U1.16 37.23,16.05 v37.21,16.07 | U1.14 36.23,16.03 v36.2,16.07
  Top 0.305: v36.2,18.29 35.84,17.93 U1.9
  Top 0.508: R41.2 41.28,29.46 v41.15,29.59
  Top 0.61: C15.1 47.19,16.13 v47.7,15.62 | C10.1 v56.52,33.4
  Bottom 0.508: P1.2 v17.53,47.75
  other vias: 38.23,22.23 8,49.53 8.13,26.54 38.23,29.59 39.75,29.59 42.8,29.59 44.33,29.59 43.06,35.31 41.28,32.89 39.63,41.53 41.66,41.53 49.53,32.38 52.2,32.38 28.96,14.48 29.72,13.84 30.86,13.46 32.77,13.46 16.26,11.3 10.8,11.3 4.19,11.3 4.19,1.27 11.18,1.27 16.26,1.27 4.19,6.35 10.8,6.35 16.26,6.35 21.91,12.89 21.91,14.22 4.19,18.41 16.13,20.7 16.13,19.56 4.19,25.4 11.18,25.4 11.18,49.53 4.19,49.53 51.82,36.45 56.77,36.45 68.33,23.5 65.79,32.38 65.79,42.55 65.79,38.1 62.61,22.23 51.31,22.23 51.39,19.05 47.75,19.56 47.75,20.83 47.63,12.06 49.53,30.73 23.37,19.81 38.23,18.29 39.3,22.21 40.01,16.13 42.04,22.73 34.29,14.1 40.03,19.71 37.21,18.29 40.03,18.26 8.38,11.3 6.1,11.3 6.1,20.7 8.38,20.7 10.8,20.7 12.96,20.7 12.96,11.3 4.19,13.34 4.19,15.88 4.19,20.7 36.07,20.57 37.09,21.34 36.5,25.81 35.49,26.95 33.71,28.85 32.18,28.85 34.85,24.79 34.09,25.55 33.2,26.44 32.18,26.95 27.36,28.6 33.07,23.27 32.18,24.41 28.32,25.04 28.3,26.86 19.48,28.6 24.31,29.11 49.1,13.21 47.7,13.21 35.1,23.65 51.18,28.83 24.77,21.72 24.77,20.45 24.77,19.18 32.51,35.56 32.51,33.27 39.37,10.29 37.34,10.29 35.82,10.29 40.9,10.29 42.55,10.29 59.18,28.45
  pour Top (isolate 0.254, rank 6): 2.29,53.34 70.87,53.34 70.87,0 2.29,0
  pour Bottom (isolate 0.254, rank 6): 2.29,53.34 70.87,53.34 70.87,0 2.29,0
LINKLED  (via drill 0.3 pad 0.64)
  Top 0.203: v44.71,10.41 44.71,12.19 42.55,14.35 42.55,15.62 42.93,16.01 U1.25
  Bottom 0.203: J8.9 13.45,29.86 19.94,23.37 25.15,23.37 26.16,22.35 26.16,13.34 32.64,6.86 42.17,6.86 44.71,9.4 v44.71,10.41
MMISO
  Bottom 0.203: U5.13 33.78,48.13 39.69,42.23 44.52,42.23 45.72,41.02 45.72,34.92 47.63,33.02 52.71,33.02 53.22,32.51 MISO.11
MMOSI
  Bottom 0.203: U5.12 36.32,46.89 40.1,43.12 45.15,43.12 46.74,41.53 46.74,35.31 48.01,34.04 54.74,34.04 56.77,32 MOSI.00
MOSI  (via drill 0.3 pad 0.64)
  Top 0.203: U2.8 55.79,26.83 55.25,26.29 55.25,16.38 54.15,15.29 J1.3 50.5,15.29 v49.66,16.13 | U1.35 42.01,21.43 v41.59,21.84
  Bottom 0.203: v41.59,21.84 42.55,20.89 42.55,18.67 43.82,17.4 48.39,17.4 v49.66,16.13
MSCK
  Bottom 0.203: U5.14 32.51,52.07 34.55,52.07 35.05,51.56 35.05,47.5 39.88,42.67 44.83,42.67 46.23,41.27 46.23,35.05 47.75,33.53 54.23,33.53 54.99,32.77 SCK.11
N$3
  Top 0.203: U4.7 28.32,27.81 | 28.32,27.81 28.32,27.56 | C20.1 28.58,27.56 | 28.58,27.56 28.32,27.56 | 28.32,27.56 28.07,27.56 | 28.07,27.56 R2.1 | 28.32,27.81 28.07,27.56 | 28.32,27.81 28.58,27.56
N$4  (via drill 0.3 pad 0.64)
  Top 0.203: U2.9 58.83,27.53 59.18,27.18 v59.44,27.18 59.95,27.69 59.95,28.96 59.57,29.34 R11.2
  Bottom 0.127: MOSI.11 MOSI.MM
  Bottom 0.203: MOSI.MM 58.42,28.19 v59.44,27.18
N$6
  Top 0.203: R10.1 SPD.+
N$7  (via drill 0.3 pad 0.64)
  Top 0.203: R12.2 v56.39,25.84 | U2.5 53.1,28.18 53.47,27.81 v53.47,25.84
  Bottom 0.127: SCK.00 SCK.MM
  Bottom 0.203: SCK.MM 55.63,28.19 55.88,27.94 55.88,26.04 | v53.47,25.84 55.69,25.84 | 55.69,25.84 55.88,25.84 | 55.88,25.84 56.07,25.84 | 56.07,25.84 v56.39,25.84 | 55.88,26.04 55.88,25.84 | 55.88,26.04 55.69,25.84 | 55.88,26.04 56.07,25.84
N$8
  Top 0.203: U4.3 C24.1
N$9
  Top 0.203: R13.2 54.99,30.86 56.2,29.65 56.26,29.59 56.38,29.48 U2.12
N$10
  Top 0.203: U6.12 42.31,37.85 41.48,38.67 39.82,38.67 38.86,39.62 R15.2
N$14
  Top 0.203: U2.3 51.42,29.48 51.37,29.53 51.31,29.59 R18.2
N$17
  Top 0.203: U6.8 39.66,34.77 R24.2
N$18
  Top 0.203: R17.1 33.53,45.34 31.94,46.93 31.88,46.99 15.5,46.99 13.47,44.96 J8.12
N$19
  Top 0.203: J8.10 13.46,33.53 16.39,30.61 16.39,28.57 17.4,27.56 R16.1
N$20
  Top 0.203: U6.6 40.36,44.8 R25.1
N$21
  Top 0.203: R25.2 41.4,46.35 41.91,45.85 W!INT.1
  Bottom 0.203: P8.1 W!INT.1
N$22
  Top 0.203: U4.1 C30.1
N$25
  Top 0.203: U4.2 C31.1 | R23.2 C31.1 | R22.2 C31.1
N$26
  Top 0.203: R28.2 PWR.+
N$27
  Top 0.203: U1.38 40.73,24.48 41.02,24.77 43.31,24.77 44.33,25.78 R37.1
N$28
  Top 0.254: R32.1 C26.2 49.41,22.23 X2.2
N$29
  Top 0.203: R26.2 33.02,40.77 32.39,41.4 32.39,44.32 31.69,45.02 31.5,45.21 30.48,46.23 22.73,46.23 21.97,45.47 U4.15
N$30
  Top 0.203: U1.39 40.23,24.74 40.71,25.21 42.87,25.21 43.56,25.91 43.56,29.84 R38.1
N$31
  Top 0.203: U1.40 39.73,25.25 40.13,25.65 42.17,25.65 42.8,26.29 R39.1
N$32
  Top 0.203: U1.41 39.23,25.52 39.82,26.1 41.59,26.1 42.04,26.54 42.04,29.84 R40.1
N$33
  Top 0.203: U1.42 38.73,25.65 39.63,26.54 40.52,26.54 R41.1
N$35
  Top 0.203: U1.43 38.23,25.79 R42.2 40.52,28.07 40.52,29.84 R46.1
N$36
  Top 0.203: U1.44 37.73,26.81 R43.2 38.99,28.07 38.99,29.84 R47.1
N$37
  Top 0.203: U1.45 37.23,26.78 R44.2 37.47,28.07 37.47,29.84 R48.1
N$42
  Top 0.203: U4.10 28.32,44.2 28.96,44.83 31.12,44.83 31.88,44.07 31.88,39.75 32.39,39.24 R19.2
N$43  (via drill 0.3 pad 0.64)
  Top 0.203: C4.2 35.94,38.99 35.69,39.24 R19.1 R26.1 v35.05,41.53 | R9.1 v24.77,44.32 | R14.1 19.18,45.97 19.56,46.35 v19.81,46.35
  Bottom 0.203: 24.77,45.34 25.02,45.34 | 25.02,45.34 34.16,45.34 35.05,44.45 v35.05,41.53 | 24.77,45.59 24.77,45.34 | 24.77,45.34 24.77,45.09 | 24.77,45.09 v24.77,44.32 | 25.02,45.34 24.77,45.59 | 25.02,45.34 24.77,45.09 | v19.81,46.35 24.26,46.35 24.77,45.85 24.77,45.59
N$50
  Top 0.203: U1.23 40.73,13.88 41.15,13.46 41.66,13.46 43.06,12.06 R31.2
N$53  (via drill 0.3 pad 0.64)
  Top 0.254: U1.26 41.75,16.93 v41.72,16.95
  Bottom 0.203: v41.72,16.95 47.88,16.95 50.1,14.73 50.1,11.46 52.04,9.53 TP6.T
N_INT
  Bottom 0.203: P8.2 59.57,45.21 60.71,46.35 U5.3
PB3/MOSI
  Top 0.203: U5.37 67.19,29.08 62.23,29.08 61.09,30.23 R11.1
PB4/MISO  (via drill 0.3 pad 0.64)
  Top 0.203: R24.1 41.66,33.66 41.91,33.4 47.88,33.4 48.9,32.38 48.9,31.75 | 48.9,31.75 48.9,31.5 | 48.9,31.5 48.9,31.24 | 48.9,31.24 48.9,28.45 49.28,28.07 R18.1 50.68,28.07 v50.8,27.94 | 49.15,31.5 53.6,31.5 54.23,32.13 54.23,33.53 54.74,34.04 62.23,34.04 U5.33 | 49.15,31.5 48.9,31.5 | 49.15,31.5 48.9,31.75 | 49.15,31.5 48.9,31.24
  Bottom 0.127: MISO.00 MISO.MM
  Bottom 0.203: MISO.MM 52.58,28.19 52.33,27.94 v50.8,27.94
PB5/SCK
  Top 0.203: U5.34 63.12,25.27 62.99,25.15 62.93,25.08 R12.1
PC4/SDA  (via drill 0.3 pad 0.64)
  Top 0.203: U5.17 24.89,49.53 v37.21,49.53
  Bottom 0.203: v37.21,49.53 37.21,46.7 40.36,43.56 46.1,43.56 49.28,40.39 I2C.2 50.28,39.37 61.6,39.37 63.63,37.34 63.63,22.99 65.15,21.46 65.15,6.48 63.25,4.57 U5.31
PC5/SCL  (via drill 0.3 pad 0.64)
  Top 0.203: U5.18 21.08,49.91 22.1,48.9 v37.85,48.9
  Bottom 0.203: v37.85,48.9 37.85,46.91 40.69,44.07 47.58,44.07 I2C.1 50.25,41.4 60.4,41.4 64.14,37.67 64.14,23.37 65.79,21.72 U5.32
PD0/RX
  Bottom 0.203: U5.1 65.79,44.58 63.58,42.37 UART.1
PD1/TX
  Top 0.203: U5.2 63.25,41.91 61.71,40.37 UART.2
PWR_IN
  Top 1.016: U5.26 48.01,8.12 D1.2
RESET
  Top 0.203: D3.- 36.64,3.87 U5.21
RST_N  (via drill 0.3 pad 0.64)
  Top 0.203: R36.1 45.09,29.84 45.09,25.65 43.69,24.26 42.8,24.26 v42.17,23.62 v42.16,23.63 U1.37 | SW1.2 24.12,6.98 25.91,8.76 D3.+ 34.29,8.76 35.05,9.53 37.21,9.53 40.64,6.1 44.96,6.1 46.1,7.24 46.1,9.4 46.87,10.16 49.15,10.16 v50.8,11.81
  Bottom 0.203: v42.17,23.62 43.06,22.73 43.06,18.8 43.94,17.91 48.9,17.91 50.8,16 v50.8,11.81
RX+  (via drill 0.3 pad 0.64)
  Top 0.203: U4.14 v23.24,44.7 R9.2
  Bottom 0.203: J8.3 17.01,36.57 17.4,36.96 17.4,42.93 18.04,43.56 21.72,43.56 22.23,44.07 22.23,44.45 22.48,44.7 v23.24,44.7
RX-  (via drill 0.3 pad 0.64)
  Top 0.203: U4.16 v20.7,44.7 R14.2
  Bottom 0.203: J8.6 16.39,39.63 16.89,40.13 16.89,43.08 17.89,44.07 18.42,44.07 18.54,44.2 18.54,45.34 18.67,45.47 19.05,45.47 19.18,45.34 19.18,44.2 19.31,44.07 21.59,44.07 21.72,44.2 21.72,44.45 21.46,44.7 v20.7,44.7
RXN  (via drill 0.3 pad 0.64)
  Top 0.203: U1.5 37.2,19.93 v37.47,20.19 | C30.2 20.7,28.83 v20.45,28.57 R23.1
  Bottom 0.203: v37.47,20.19 37.21,19.94 34.93,19.94 34.29,20.57 34.29,24.26 32.31,26.24 27.1,26.24 26.67,26.67 26.67,29.84 25.66,30.86 22.61,30.86 21.85,30.1 21.85,28.96 21.46,28.57 v20.45,28.57
RXP  (via drill 0.3 pad 0.64)
  Top 0.203: U1.6 37.22,19.43 v37.47,19.18 | R22.1 v23.5,28.57 23.24,28.83 C24.2
  Bottom 0.203: v37.47,19.18 37.21,19.43 34.8,19.43 33.78,20.45 33.78,24 32.01,25.78 26.93,25.78 26.16,26.54 26.16,29.72 25.53,30.35 22.73,30.35 22.35,29.97 22.35,28.19 22.61,27.94 23.12,27.94 23.5,28.32 v23.5,28.57
SCK  (via drill 0.3 pad 0.64)
  Top 0.203: U1.33 43.78,20.43 44.07,20.72 44.07,22.39 v43.89,22.57 | U2.6 51.47,27.53 50.74,26.8 v49.28,26.8 | J1.5 53.86,13.09 v53.98,13.21
  Bottom 0.203: v53.98,13.21 53.98,17.91 49.32,22.57 | v49.28,26.8 49.28,22.73 | 49.28,22.73 49.28,22.61 49.32,22.57 | v43.89,22.57 49.11,22.57 | 49.11,22.57 49.32,22.57 | 49.11,22.57 49.28,22.73
SCS_N  (via drill 0.3 pad 0.64)
  Top 0.203: U1.32 43.86,19.93 44.58,20.64 44.58,22.99 | U6.11 41.66,35.69 41.53,35.56 v41.02,35.56 41.01,35.58 U6.10 | 44.58,22.99 44.58,23.11 | 44.58,23.11 v44.45,23.24 | 44.58,23.11 44.71,23.11 | 44.71,23.11 47.63,23.11 R34.1 | 44.71,23.11 44.58,22.99
  Bottom 0.203: v41.02,35.56 41.02,34.16 41.91,33.27 41.91,25.78 v44.45,23.24
TCS
  Top 0.203: U2.1 54.1,30.83 54.74,30.19 54.74,29.08 | U2.11 54.99,28.83 | 54.99,28.83 54.74,28.83 | 54.74,28.57 54.74,18.03 54.74,17.91 54.74,17.02 54.11,16.39 J1.2 | 54.74,28.57 54.74,28.83 | 54.74,28.83 54.74,29.08 | 54.99,28.83 54.74,29.08 | 54.99,28.83 54.74,28.57
TFSS
  Top 0.203: R13.1 53.47,47.5 55.63,49.66 U5.5
TMISO  (via drill 0.3 pad 0.64)
  Top 0.203: U2.2 53.72,30.13 54.23,29.62 54.23,20.45 v54.1,20.32 | v55.25,14.48 55.25,11.56 54.58,10.89 J1.7
  Bottom 0.203: v55.25,14.48 55.25,19.18 v54.1,20.32
TOCAP
  Top 0.203: U1.20 39.23,13.58 38.36,12.7 C28.2
TX+  (via drill 0.3 pad 0.64)
  Top 0.203: U4.9 v29.59,43.94
  Bottom 0.203: J8.1 17.51,34.53 18.54,35.56 18.54,42.09 19,42.55 28.07,42.55 28.58,43.05 28.58,43.69 28.83,43.94 v29.59,43.94
TX-  (via drill 0.3 pad 0.64)
  Top 0.203: U4.11 v27.05,43.94
  Bottom 0.203: J8.2 17.39,35.55 18.04,36.2 18.04,42.24 18.85,43.05 27.82,43.05 28.07,43.31 28.07,43.88 27.88,44.07 27.18,44.07 v27.05,43.94
TXN  (via drill 0.3 pad 0.64)
  Top 0.203: U1.1 35.01,21.93 v35.31,22.23 | U4.6 v27.05,32.38 R20.1
  Bottom 0.203: v35.31,22.23 35.56,21.97 35.94,21.97 36.2,22.23 36.2,24.51 33.02,27.69 28.96,27.69 28.07,28.57 28.07,32.38 27.82,32.64 27.31,32.64 v27.05,32.38
TXP  (via drill 0.3 pad 0.64)
  Top 0.203: U1.2 35.09,21.43 v35.31,21.21 | U4.8 v29.59,32.38 R21.1
  Bottom 0.203: v29.59,32.38 28.58,31.37 28.58,28.7 29.09,28.19 33.15,28.19 36.71,24.64 36.71,22.1 36.07,21.46 35.56,21.46 v35.31,21.21
WINT_N  (via drill 0.3 pad 0.64)
  Top 0.203: U1.36 42.93,22.86 44.07,24 R35.1 v45.47,24.77 | U6.5 41.01,39.32 v41.02,39.31
  Bottom 0.203: v41.02,39.31 42.17,38.16 42.17,33.78 45.47,30.48 v45.47,24.77
WMISO  (via drill 0.3 pad 0.64)
  Top 0.203: U6.9 40.36,37.94 v40.39,37.97 | U1.34 40.41,20.93 v40.39,20.9
  Bottom 0.203: v40.39,20.9 v40.39,37.97
WSS
  Top 0.203: R15.1 U5.11
XI
  Top 0.254: U1.30 44.19,18.93 R33.2 C25.2 49.41,17.65 X2.1
XO
  Top 0.254: U1.31 44.07,19.43 | 44.07,19.43 44.19,19.43 R32.2 R33.1 | 44.08,19.43 44.07,19.43

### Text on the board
bPlace: W5500 Ethernet Shield | v1.0 08/28/2014 | by Seeed Studio | www.seeedstudio.com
